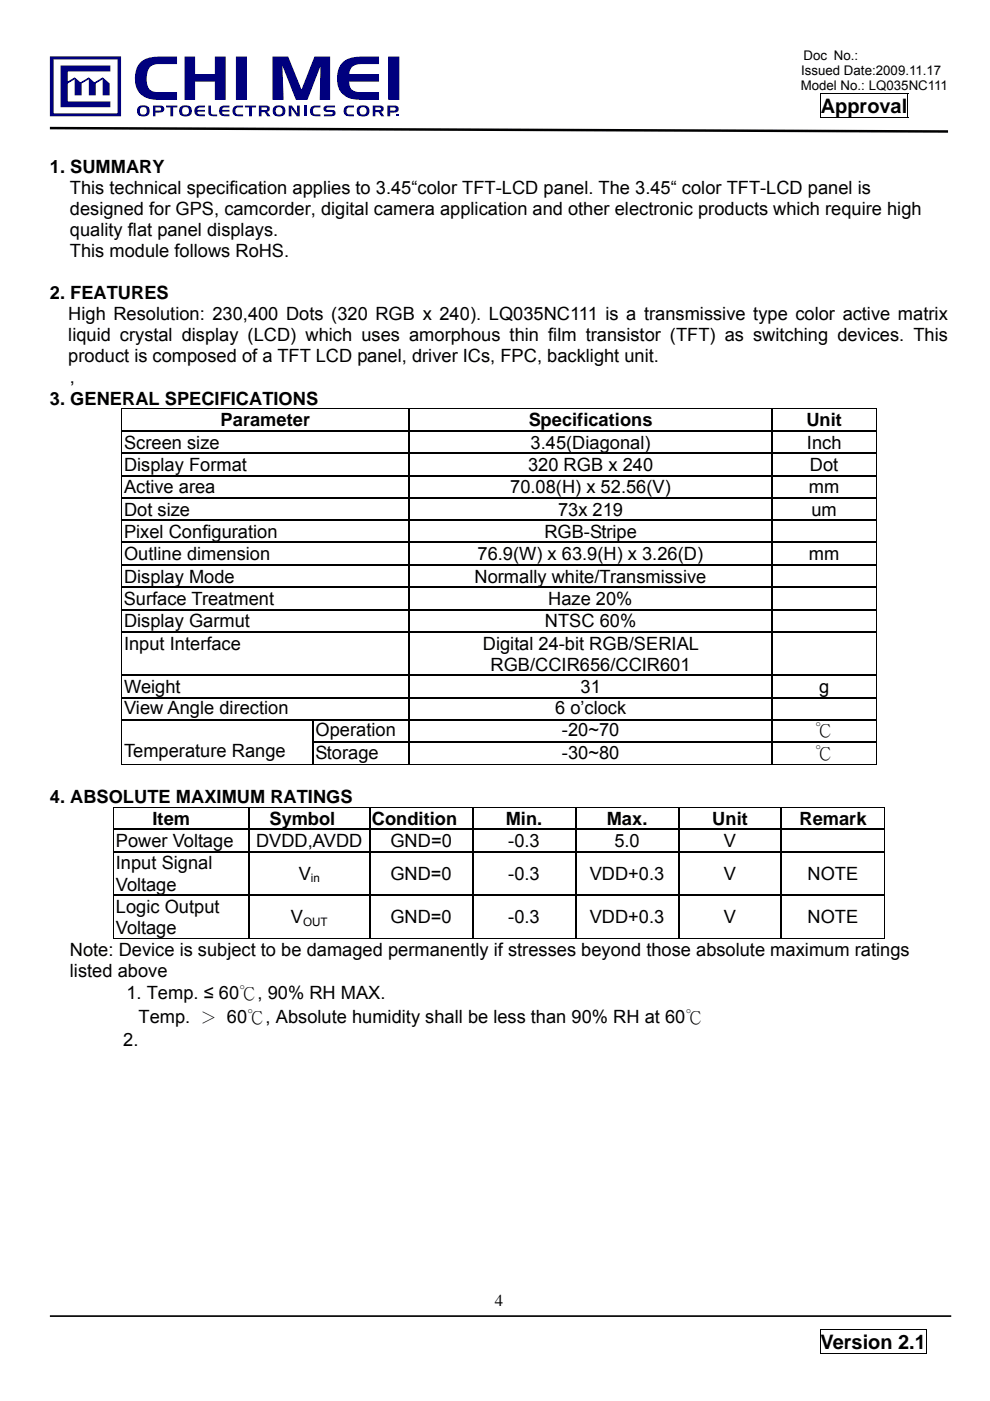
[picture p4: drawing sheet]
<svg xmlns="http://www.w3.org/2000/svg" width="210mm" height="297mm" viewBox="0 0 210 297" stroke-linecap="round" stroke-linejoin="round" font-family="sans-serif">
<defs><g id="words">
<g font-size="4.2">
<text x="174.1" y="23.9">Approval</text>
<text x="174.1" y="285.9">Version 2.1</text>
</g>
<g font-size="3.9">
<text x="10.6" y="36.7">1. SUMMARY</text>
<text x="14.8" y="41.1">This technical specification applies to 3.45“color TFT-LCD panel. The 3.45“ color TFT-LCD panel is</text>
<text x="14.8" y="45.6">designed for GPS, camcorder, digital camera application and other electronic products which require high</text>
<text x="14.8" y="50.1">quality flat panel displays.</text>
<text x="14.8" y="54.5">This module follows RoHS.</text>
<text x="10.6" y="63.5">2. FEATURES</text>
<text x="14.5" y="67.9">High Resolution: 230,400 Dots (320 RGB x 240). LQ035NC111 is a transmissive type color active matrix</text>
<text x="14.5" y="72.4">liquid crystal display (LCD) which uses amorphous thin film transistor (TFT) as switching devices. This</text>
<text x="14.5" y="76.8">product is composed of a TFT LCD panel, driver ICs, FPC, backlight unit.</text>
<text x="14.8" y="81.3">,</text>
<text x="10.6" y="85.8">3. GENERAL SPECIFICATIONS</text>
<text x="26.3" y="95.1">Screen size</text>
<text x="46.8" y="90.4">Parameter</text>
<text x="112.2" y="90.4">Specifications</text>
<text x="112.5" y="95.1">3.45(Diagonal)</text>
<text x="171" y="90.4">Unit</text>
<text x="171.2" y="95.1">Inch</text>
<text x="26.3" y="99.9">Display Format</text>
<text x="112" y="99.9">320 RGB x 240</text>
<text x="171.8" y="99.9">Dot</text>
<text x="26.3" y="104.6">Active area</text>
<text x="108.2" y="104.6">70.08(H) x 52.56(V)</text>
<text x="171.6" y="104.6">mm</text>
<text x="26.3" y="109.3">Dot size</text>
<text x="118.4" y="109.3">73x 219</text>
<text x="172.1" y="109.3">um</text>
<text x="26.3" y="114">Pixel Configuration</text>
<text x="26.3" y="118.8">Outline dimension</text>
<text x="101.3" y="118.8">76.9(W) x 63.9(H) x 3.26(D)</text>
<text x="115.5" y="114">RGB-Stripe</text>
<text x="171.5" y="118.8">mm</text>
<text x="26.3" y="123.5">Display Mode</text>
<text x="100.7" y="123.5">Normally white/Transmissive</text>
<text x="26.2" y="128.2">Surface Treatment</text>
<text x="116.3" y="128.2">Haze 20%</text>
<text x="26.3" y="133">Display Garmut</text>
<text x="26.3" y="137.8">Input Interface</text>
<text x="102.4" y="137.8">Digital 24-bit RGB/SERIAL</text>
<text x="115.6" y="133">NTSC 60%</text>
<text x="104" y="142.2">RGB/CCIR656/CCIR601</text>
<text x="26.3" y="147">Weight</text>
<text x="123.1" y="147">31</text>
<text x="173.7" y="147">g</text>
<text x="26.3" y="151.4">View Angle direction</text>
<text x="117.7" y="151.4">6 o’clock</text>
<text x="26.3" y="160.6">Temperature Range</text>
<text x="66.9" y="160.9">Storage</text>
<text x="66.9" y="156.1">Operation</text>
<text x="119.2" y="160.9">-30~80</text>
<text x="119.2" y="156.1">-20~70</text>
<text x="172.9" y="160.9">℃</text>
<text x="172.9" y="156.1">℃</text>
<text x="10.6" y="170.2">4. ABSOLUTE MAXIMUM RATINGS</text>
<text x="24.6" y="179.6">Power Voltage</text>
<text x="32.3" y="174.9">Item</text>
<text x="54.3" y="179.6">DVDD,AVDD</text>
<text x="57.2" y="174.9">Symbol</text>
<text x="78.9" y="174.9">Condition</text>
<text x="82.8" y="179.6">GND=0</text>
<text x="107.3" y="174.9">Min.</text>
<text x="107.8" y="179.6">-0.3</text>
<text x="128.7" y="174.9">Max.</text>
<text x="130.3" y="179.6">5.0</text>
<text x="151.1" y="174.9">Unit</text>
<text x="153.5" y="179.6">V</text>
<text x="169.6" y="174.9">Remark</text>
<text x="24.6" y="184.3">Input Signal</text>
<text x="24.6" y="188.8">Voltage</text>
<text x="63.4" y="186.6">V</text>
<text x="82.8" y="186.6">GND=0</text>
<text x="107.8" y="186.6">-0.3</text>
<text x="125.1" y="186.6">VDD+0.3</text>
<text x="153.5" y="186.6">V</text>
<text x="171.3" y="186.6">NOTE</text>
<text x="24.6" y="193.5">Logic Output</text>
<text x="24.6" y="198">Voltage</text>
<text x="61.7" y="195.7">V</text>
<text x="82.8" y="195.7">GND=0</text>
<text x="107.8" y="195.7">-0.3</text>
<text x="125.1" y="195.7">VDD+0.3</text>
<text x="153.5" y="195.7">V</text>
<text x="171.3" y="195.7">NOTE</text>
<text x="14.8" y="202.6">Note: Device is subject to be damaged permanently if stresses beyond those absolute maximum ratings</text>
<text x="14.8" y="207.1">listed above</text>
<text x="26.8" y="211.9">1. Temp. ≤ 60℃, 90% RH MAX.</text>
<text x="26.1" y="221.8">2.</text>
<text x="29.4" y="216.8">Temp. ＞ 60℃, Absolute humidity shall be less than 90% RH at 60℃</text>
</g>
<text font-size="3.5" x="104.9" y="276.9">4</text>
<g font-size="2.8">
<text x="169.9" y="15.9">Issued Date:2009.11.17</text>
<text x="170.4" y="12.6">Doc No.:</text>
<text x="169.8" y="19.1">Model No.: LQ035NC111</text>
</g>
<g font-size="2.5">
<text x="65.9" y="187.1">in</text>
<text x="64.3" y="196.3">OUT</text>
</g>
</g></defs>
<path d="M173.9 19.7h.2v.2h-.2zM192.4 19.7h.2v.2h-.2zM173.9 24.8h.2v.1h-.2zM192.4 24.8h.2v.1h-.2zM173.9 281.8h.2v.2h-.2zM173.9 286.9h.2v.1h-.2zM196.4 281.8h.2v.2h-.2zM196.4 286.9h.2v.1h-.2z" fill="#000"/>
<path d="M173.9 19.8h18.7M174 19.9v4.9M192.5 19.9v4.9M173.9 24.8h18.7M173.9 281.9h22.7M173.9 286.9h22.7M174 282v4.9M196.5 282v4.9" fill="none" stroke="#000" stroke-width=".21"/>
<g fill="#00007e">
<path d="M29.3 22.7h.1a1.61 1.61 0 0 1 1.6-.3 1 1 0 0 1 .7 .9v.5a1.02 1.02 0 0 1-1.1 .9h-.5a.98 .98 0 0 1-1-.9zM29.6 23.5a.8 .8 0 0 0 1.6 0 .8 .8 0 0 0-1.6 0z" fill-rule="evenodd"/>
<path d="M32.4 22.4h1.4a.87 .87 0 0 1 1.1 .6l-.3 .6-.4 .2-1.2 .1v.8h-.6zM33 22.8v.7h.9l.3-.3a.41 .41 0 0 0-.5-.4z" fill-rule="evenodd"/>
<path d="M35.2 22.4h2.4v.4h-.9v1.9h-.6v-1.9h-.9z" fill-rule="evenodd"/>
<path d="M38.2 22.7l.5-.3 .9-.1 .5 .1 .5 .4 .1 .5-.1 .9-.5 .4-1.1 .1a1.06 1.06 0 0 1-1-.9zM38.6 23.5a.78 .78 0 0 0 1.5 0 .78 .78 0 0 0-1.5 0z" fill-rule="evenodd"/>
<path d="M41.4 22.7l.7-.3h1.4v.4h-1.2l-.4 .3v.2h1.6v.4h-1.6v.4l.4 .2h1.2v.4l-1.5-.1a1.17 1.17 0 0 1-.6-1.9z" fill-rule="evenodd"/>
<path d="M44.2 22.4h.5l.1 1.7 .2 .2h1.1v.4l-1.4-.1-.4-.3z" fill-rule="evenodd"/>
<path d="M46.8 22.6l.5-.2h1.4v.4h-1.2l-.4 .3v.2h1.6v.4h-1.6l.3 .5 1.3 .1v.4l-1.7-.1a.94 .94 0 0 1-.5-1.2l.1-.5z" fill-rule="evenodd"/>
<path d="M49.6 22.6l.5-.2h1.5v.4h-1.4l-.3 .5 .2 .8 .3 .2h1.2v.4l-1.6-.1-.5-.3-.2-.9z" fill-rule="evenodd"/>
<path d="M51.9 22.4h2.4v.4h-.9v1.9h-.6v-1.9h-.9z" fill-rule="evenodd"/>
<path d="M55.5 22.8v.5h.7a.31 .31 0 0 0 .4-.1 .31 .31 0 0 0-.2-.4zM54.9 22.4h1.5a.67 .67 0 0 1 .8 .5 .67 .67 0 0 1-.5 .8l.7 1h-.7l-.6-.9h-.6v.9h-.6z" fill-rule="evenodd"/>
<path d="M58.1 22.7a1.68 1.68 0 0 1 1.9-.2l.2 .1a1.45 1.45 0 0 1 .3 1.5l-.6 .5-1 .1a1.18 1.18 0 0 1-1.1-.9v-.6zM58.4 23.5a.8 .8 0 0 0 1.6 0 .8 .8 0 0 0-1.6 0z" fill-rule="evenodd"/>
<path d="M61.2 22.4h.7l1.2 1.6-.1-1.6h.6v2.3h-.7l-1.1-1.8v1.8h-.6z" fill-rule="evenodd"/>
<path d="M66 22.7l.6-.3h1.4v.4h-1.2l-.4 .3v.8l.2 .3 1.4 .1v.4h-1a1.07 1.07 0 0 1-1.3-.9v-.5z" fill-rule="evenodd"/>
<path d="M68.6 22.7l.6-.3h1.9v.4h-1.6l-.3 .4 .2 .1h1.3l.4 .4a.67 .67 0 0 1 0 .7 .67 .67 0 0 1-.7 .3h-1.7v-.4h1.6a.27 .27 0 0 0 .3-.3 .27 .27 0 0 0-.2-.3h-1.2a.74 .74 0 0 1-.6-1z" fill-rule="evenodd"/>
<path d="M73.2 22.6l.5-.2h1.4v.4h-1a.87 .87 0 0 0-.5 1.3l.4 .2h1.1v.4l-1.5-.1-.5-.3-.2-.9z" fill-rule="evenodd"/>
<path d="M76 22.6l.5-.2h1l.5 .2 .3 .5v.8l-.2 .5-.4 .2-.9 .1a1.03 1.03 0 0 1-1.1-.9v-.6zM76.3 23.5a.79 .79 0 0 0 1.5 0 .79 .79 0 0 0-1.5 0z" fill-rule="evenodd"/>
<path d="M79.6 22.8v.5l1.2-.1-.1-.4zM79.1 22.4h1.6l.5 .2 .2 .6-.2 .3-.4 .2 .7 1h-.6l-.6-.9h-.7v.9h-.5z" fill-rule="evenodd"/>
<path d="M82.2 22.4h1.3a.81 .81 0 0 1 1 .5l.1 .4-.4 .5-1.4 .1v.8h-.6zM82.8 22.8v.7h.8l.3-.2-.1-.4z" fill-rule="evenodd"/>
<path d="M12.8 13.9h10.6v1.3h-9v2.1l1.4-.9 1.3 1.1 1.7-1.1 1.2 1.1 1.8-1.1 1.5 1.3v2.5h-1.5v-3.4l-1.5 .9v2.5h-1.5v-3.4l-1.5 .9v2.5h-1.5v-3.4l-1.4 .9v3.8h9v1.2h-10.6zM10.6 12h15.1v12.7h-15.1zM11.4 12.6v11.4h13.5v-11.4z" fill-rule="evenodd"/>
<path d="M29.9 13.1l.4-.3a6 6 0 0 1 3.1-.8h4.1v1.6h-3.7a2.27 2.27 0 0 0-2.6 2.3l-.1 .7a2.38 2.38 0 0 0 1.8 2.9h4.6v1.7h-4.1a4.5 4.5 0 0 1-4.6-6.1l.4-1.1zM39.1 12h2.3v3.7h4.2v-3.7h2.3v9.2h-2.3v-3.9h-4.2v3.9h-2.3zM50 12h2.4v9.2h-2.4zM57.8 12h3.3l2.8 7 2.8-7h3.3v9.2h-2.2l.2-7.2-2.8 7.2h-2.4l-2.9-7.3 .3 7.3h-2.4zM72.6 13.3a5 5 0 0 1 3.7-1.3h4.1v1.6h-3.7a2.21 2.21 0 0 0-2.3 1.1l-.3 1h6.3v1.6h-6.3a2.02 2.02 0 0 0 2.4 2.2h3.9v1.7h-4.2a4.3 4.3 0 0 1-4.7-5.3l.4-1.4zM82.3 12h2.4v9.2h-2.4z" fill-rule="evenodd"/>
</g>
<g fill="#00007e">
<path d="M64.5 22.4h.6v2.3h-.6z"/>
<path d="M84 24.3h.5v.4h-.5z"/>
</g>
<path d="M10.6 27.2l190.5 .7" fill="none" stroke="#000" stroke-width=".53"/>
<path d="M10.6 279h191.2" fill="none" stroke="#000" stroke-width=".35"/>
<g fill="#000">
<path d="M25.7 86.6h.2v.2h-.2zM25.7 91.3h.2v.2h-.2zM25.7 96h.2v.3h-.2zM86.7 91.3h.2v.2h-.2zM86.7 96h.2v.3h-.2zM163.7 91.3h.2v.2h-.2zM163.7 96h.2v.3h-.2zM185.8 86.6h.1v.2h-.1zM185.8 91.3h.1v.2h-.1zM185.8 96h.1v.3h-.1zM25.7 100.7h.2v.3h-.2zM25.7 105.5h.2v.2h-.2z"/>
<path d="M25.7 110.2h.2v.2h-.2zM25.7 114.9h.2v.3h-.2zM25.7 119.6h.2v.3h-.2zM86.7 100.7h.2v.3h-.2zM86.7 105.5h.2v.2h-.2zM86.7 110.2h.2v.2h-.2zM86.7 114.9h.2v.3h-.2zM86.7 119.6h.2v.3h-.2zM163.7 100.7h.2v.3h-.2zM163.7 105.5h.2v.2h-.2zM163.7 110.2h.2v.2h-.2zM163.7 114.9h.2v.3h-.2z"/>
<path d="M163.7 119.6h.2v.3h-.2zM185.8 100.7h.1v.3h-.1zM185.8 105.5h.1v.2h-.1zM185.8 110.2h.1v.2h-.1zM185.8 114.9h.1v.3h-.1zM185.8 119.6h.1v.3h-.1zM25.7 124.4h.1v.2h-.1zM25.7 129.4h.2zM25.7 133.9h.2v.3h-.2zM86.6 124.4h.2v.2h-.2zM86.7 129.4h.2zM86.7 133.9h.2v.3h-.2z"/>
<path d="M163.6 124.4h.3v.2h-.3zM163.7 129.4h.2zM163.7 133.9h.2v.3h-.2zM185.8 124.4h.2v.2h-.2zM185.8 129.4h.1zM185.8 129.2h.2v.2h-.2zM185.8 133.9h.1v.3h-.1zM185.8 124.6h.2zM25.7 143.1h.2v.3h-.2zM25.7 147.8h.2v.3h-.2zM25.7 152.5h.2v.3h-.2zM25.7 157.3h.2v.2h-.2z"/>
<path d="M66.3 152.5h.2v.3h-.2zM66.3 157.3h.2v.2h-.2zM86.7 143.1h.2v.3h-.2zM86.7 147.8h.2v.3h-.2zM86.7 152.5h.2v.3h-.2zM86.7 157.3h.2v.2h-.2zM163.7 143.1h.2v.3h-.2zM163.7 147.8h.2v.3h-.2zM163.7 152.5h.2v.3h-.2zM163.7 157.3h.2v.2h-.2zM185.8 143.1h.1v.3h-.1zM185.8 147.8h.1v.3h-.1z"/>
<path d="M185.8 152.5h.1v.3h-.1zM185.8 157.3h.1v.2h-.1zM24 171.1h.2v.2h-.2zM24 175.7h.2v.3h-.2zM52.7 175.7h.2v.3h-.2zM78.3 175.7h.2v.3h-.2zM100.1 175.7h.3v.3h-.3zM122 175.7h.2v.3h-.2zM143.8 175.7h.2v.3h-.2zM165.6 175.7h.3v.3h-.3zM185.8 162h.1v.2h-.1zM187.5 171.1h.2v.2h-.2z"/>
<path d="M187.5 175.7h.2v.3h-.2zM24 180.5h.2v.2h-.2zM24 189.7h.2v.2h-.2zM52.7 180.5h.2v.2h-.2zM52.7 189.7h.2v.2h-.2zM78.3 180.5h.2v.2h-.2zM78.3 189.7h.2v.2h-.2zM100.1 180.5h.3v.2h-.3zM100.1 189.7h.3v.2h-.3zM122 180.5h.2v.2h-.2zM122 189.7h.2v.2h-.2zM143.8 180.5h.2v.2h-.2z"/>
<path d="M143.8 189.7h.2v.2h-.2zM165.6 180.5h.3v.2h-.3zM165.6 189.7h.3v.2h-.3zM187.5 180.5h.2v.2h-.2zM187.5 189.7h.2v.2h-.2zM187.5 198.8h.2v.2h-.2z"/>
</g>
<g fill="none" stroke="#000" stroke-width=".21">
<path d="M25.7 86.7h160.2M25.8 86.8v4.5M25.8 91.5v4.5M25.8 96.3v4.4M185.8 86.8v4.5M185.8 91.5v4.5M185.8 96.3v4.4M25.8 101v4.5M25.8 105.7v4.5M25.8 110.4v4.5M25.8 115.2v4.4M25.8 119.9v4.5"/>
<path d="M185.8 101v4.5M185.8 105.7v4.5M185.8 110.4v4.5M185.8 115.2v4.4M185.8 119.9v4.5M25.8 124.6v4.6M25.8 129.4v4.5M25.8 134.2v8.9M185.8 129.4v4.5M185.8 134.2v8.9M185.9 124.6v4.6M25.8 143.4v4.4"/>
<path d="M25.8 148.1v4.4M25.8 152.8v4.5M25.8 157.5v4.7M185.8 143.4v4.4M185.8 148.1v4.4M185.8 152.8v4.5M185.8 157.5v4.7M24 171.2h163.7M24.1 171.3v4.4M24.1 176v4.5M25.7 162.1h160.1M187.6 171.3v4.4"/>
<path d="M187.6 176v4.5M24 198.9h163.5M24.1 180.7v9M24.1 189.9v9.1M187.6 180.7v9M187.6 189.9v9.1"/>
</g>
<g fill="none" stroke="#000" stroke-width=".25">
<path d="M25.9 91.4h60.8M25.9 96.1h60.8M86.8 86.8v4.5M86.8 91.5v4.5M86.8 96.3v4.4M86.9 91.4h76.8M86.9 96.1h76.8M163.8 86.8v4.5M163.8 91.5v4.5M163.8 96.3v4.4M163.9 91.4h21.9M163.9 96.1h21.9"/>
<path d="M25.9 100.8h60.8M25.9 105.6h60.8M25.9 110.3h60.8M25.9 115h60.8M25.9 119.8h60.8M86.8 101v4.5M86.8 105.7v4.5M86.8 110.4v4.5M86.8 115.2v4.4M86.8 119.9v4.5M86.9 100.8h76.8M86.9 105.6h76.8"/>
<path d="M86.9 110.3h76.8M86.9 115h76.8M86.9 119.8h76.8M163.8 101v4.5M163.8 105.7v4.5M163.8 110.4v4.5M163.8 115.2v4.4M163.8 119.9v4.5M163.9 100.8h21.9M163.9 105.6h21.9M163.9 110.3h21.9M163.9 115h21.9"/>
<path d="M163.9 119.8h21.9M25.7 129.3h160.1M25.8 124.5h60.8M25.9 134h60.8M86.7 124.6v4.6M86.8 129.4v4.5M86.8 134.2v8.9M86.8 124.5h76.8M86.9 134h76.8M163.7 124.6v4.6M163.8 129.4v4.5M163.8 134.2v8.9"/>
<path d="M163.9 124.5h21.9M163.9 134h21.9M25.9 143.2h60.8M25.9 147.9h60.8M25.9 152.7h40.4M66.4 152.8v4.5M66.4 157.5v4.5M66.5 152.7h20.2M66.5 157.4h20.2M86.8 143.4v4.4M86.8 148.1v4.4M86.8 152.8v4.5"/>
<path d="M86.8 157.5v4.5M86.9 143.2h76.8M86.9 147.9h76.8M86.9 152.7h76.8M86.9 157.4h76.8M163.8 143.4v4.4M163.8 148.1v4.4M163.8 152.8v4.5M163.8 157.5v4.5M163.9 143.2h21.9M163.9 147.9h21.9M163.9 152.7h21.9"/>
<path d="M163.9 157.4h21.9M24.2 175.9h28.5M52.8 171.3v4.4M52.8 176v4.5M52.9 175.9h25.4M78.4 171.3v4.4M78.4 176v4.5M78.5 175.9h21.6M100.2 171.3v4.4M100.2 176v4.5M100.4 175.9h21.6M122.1 171.3v4.4"/>
<path d="M122.1 176v4.5M122.2 175.9h21.6M143.9 171.3v4.4M143.9 176v4.5M144 175.9h21.6M165.8 171.3v4.4M165.8 176v4.5M165.9 175.9h21.6M24.2 180.6h28.5M24.2 189.8h28.5M52.8 180.7v9M52.8 189.9v8.9"/>
<path d="M52.9 180.6h25.4M52.9 189.8h25.4M78.4 180.7v9M78.4 189.9v8.9M78.5 180.6h21.6M78.5 189.8h21.6M100.2 180.7v9M100.2 189.9v8.9M100.4 180.6h21.6M100.4 189.8h21.6M122.1 180.7v9M122.1 189.9v8.9"/>
<path d="M122.2 180.6h21.6M122.2 189.8h21.6M143.9 180.7v9M143.9 189.9v8.9M144 180.6h21.6M144 189.8h21.6M165.8 180.7v9M165.8 189.9v8.9M165.9 180.6h21.6M165.9 189.8h21.6"/>
</g>
<use href="#words"/>
</svg>
